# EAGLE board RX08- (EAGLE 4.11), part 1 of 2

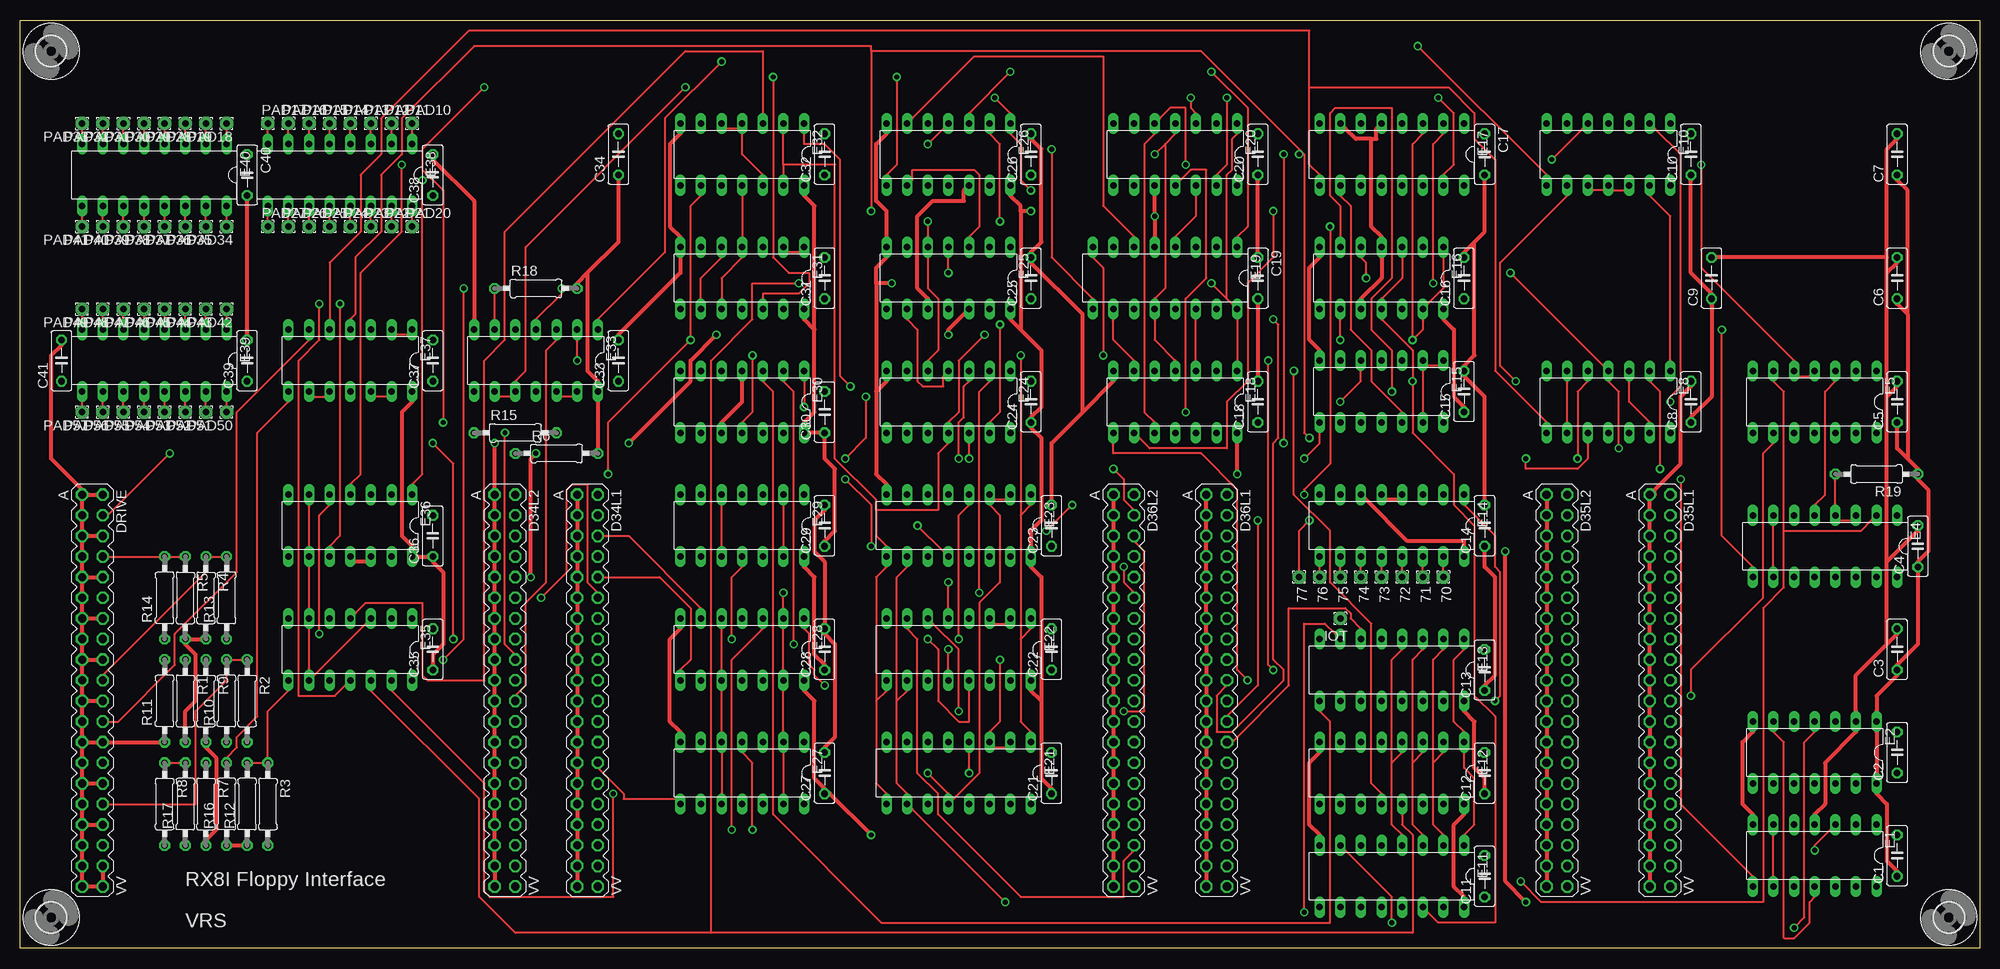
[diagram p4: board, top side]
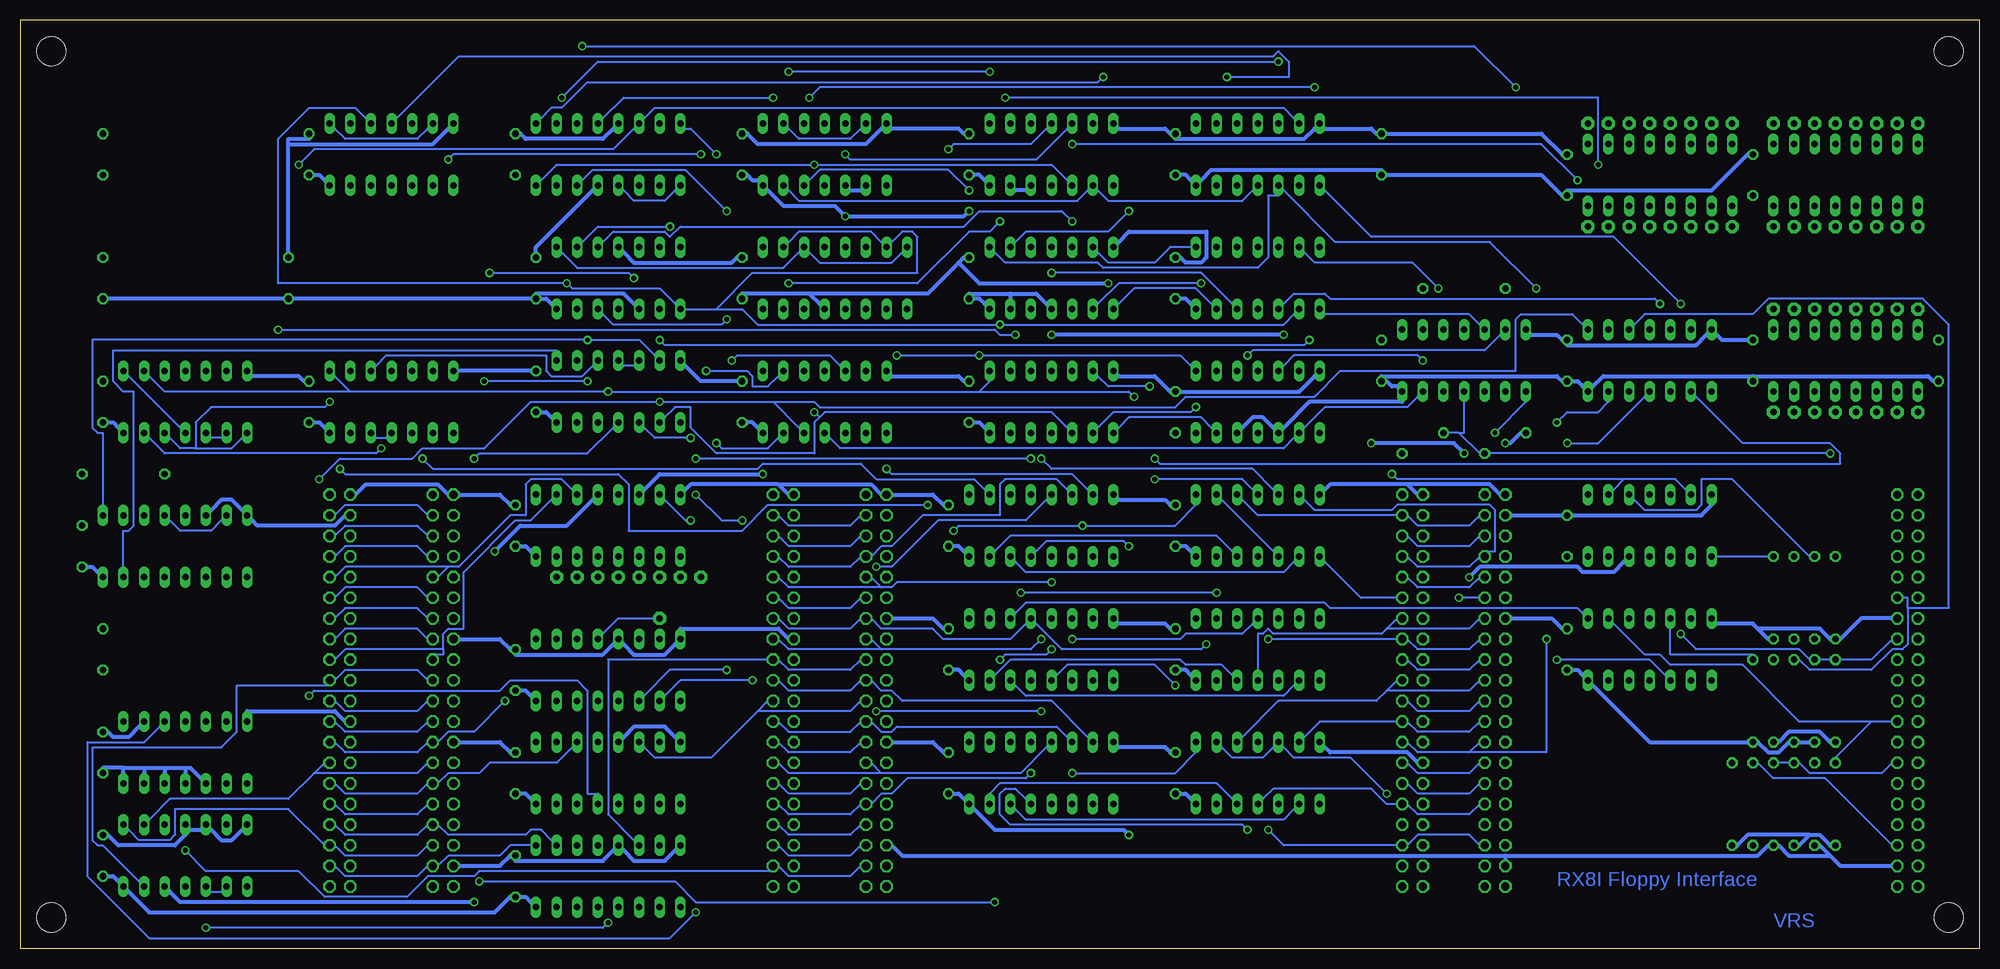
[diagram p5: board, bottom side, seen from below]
Size 241.3 x 114.3 mm. Coordinates in mm from the lower left corner, seen from the top.
Outline: 0,0 0,114.3 241.3,114.3 241.3,0 0,0
Copper layers (1*16): Top 0.035mm / dielectric 1.5mm / Bottom 0.035mm
Design rules "olimex10mil": minimum track width 10mil, minimum drill 24mil, track to track 10mil, track to pad 10mil, pad to pad 10mil, via to via 10mil, smd to smd 10mil, copper to edge 25mil, drill to drill 10mil, minimum pad ring 10mil, minimum via ring 8mil, stop-mask expansion 0mil, vias tented up to drill 0mil, thermal gap 10mil
Net classes: 1 supply: width 0.508 mm

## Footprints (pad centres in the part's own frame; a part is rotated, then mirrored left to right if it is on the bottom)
1,6/0,8 = drill 0.813 pad 1.6 octagon: 1 0,0
C050-025X075 = drill 0.813 octagon: 1 -2.54,0; 2 2.54,0
DEC40PIN = drill 1.016 octagon: A -24.13,-1.27; AA 3.81,-1.27; B -24.13,1.27; BB 3.81,1.27; C -21.59,-1.27; CC 6.35,-1.27; D -21.59,1.27; DD 6.35,1.27; E -19.05,-1.27; EE 8.89,-1.27; F -19.05,1.27; FF 8.89,1.27; H -16.51,-1.27; HH 11.43,-1.27; J -16.51,1.27; JJ 11.43,1.27; K -13.97,-1.27; KK 13.97,-1.27; L -13.97,1.27; LL 13.97,1.27; M -11.43,-1.27; MM 16.51,-1.27; N -11.43,1.27; NN 16.51,1.27; P -8.89,-1.27; PP 19.05,-1.27; R -8.89,1.27; RR 19.05,1.27; S -6.35,-1.27; SS 21.59,-1.27; T -6.35,1.27; TT 21.59,1.27; U -3.81,-1.27; UU 24.13,-1.27; V -3.81,1.27; VV 24.13,1.27; W -1.27,-1.27; X -1.27,1.27; Y 1.27,-1.27; Z 1.27,1.27
DIL14 = drill 0.813 long: 1 -7.62,-3.81; 2 -5.08,-3.81; 3 -2.54,-3.81; 4 0,-3.81; 5 2.54,-3.81; 6 5.08,-3.81; 7 7.62,-3.81; 8 7.62,3.81; 9 5.08,3.81; 10 2.54,3.81; 11 0,3.81; 12 -2.54,3.81; 13 -5.08,3.81; 14 -7.62,3.81
DIL16 = drill 0.813 long: 1 -8.89,-3.81; 2 -6.35,-3.81; 3 -3.81,-3.81; 4 -1.27,-3.81; 5 1.27,-3.81; 6 3.81,-3.81; 7 6.35,-3.81; 8 8.89,-3.81; 9 8.89,3.81; 10 6.35,3.81; 11 3.81,3.81; 12 1.27,3.81; 13 -1.27,3.81; 14 -3.81,3.81; 15 -6.35,3.81; 16 -8.89,3.81
0207/10 = drill 0.813 octagon: 1 -5.08,0; 2 5.08,0
3,6 = hole 3.6: 0,0

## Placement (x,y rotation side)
70  [1,6/0,8]  175.26,45.72 270 top
71  [1,6/0,8]  172.72,45.72 270 top
72  [1,6/0,8]  170.18,45.72 270 top
73  [1,6/0,8]  167.64,45.72 270 top
74  [1,6/0,8]  165.1,45.72 270 top
75  [1,6/0,8]  162.56,45.72 270 top
76  [1,6/0,8]  160.02,45.72 270 top
77  [1,6/0,8]  157.48,45.72 270 top
C1  0.1  [C050-025X075]  231.14,11.43 90 top
C2  0.1  [C050-025X075]  231.14,24.13 90 top
C3  0.1  [C050-025X075]  231.14,36.83 90 top
C4  0.1  [C050-025X075]  233.68,49.53 90 top
C5  0.1  [C050-025X075]  231.14,67.31 90 top
C6  0.1  [C050-025X075]  231.14,82.55 90 top
C7  0.1  [C050-025X075]  231.14,97.79 90 top
C8  0.1  [C050-025X075]  205.74,67.31 90 top
C9  0.1  [C050-025X075]  208.28,82.55 90 top
C10  0.1  [C050-025X075]  205.74,97.79 90 top
C11  0.1  [C050-025X075]  180.34,8.89 90 top
C12  0.1  [C050-025X075]  180.34,21.59 90 top
C13  0.1  [C050-025X075]  180.34,34.29 90 top
C14  0.1  [C050-025X075]  180.34,52.07 90 top
C15  0.1  [C050-025X075]  177.8,68.58 90 top
C16  0.1  [C050-025X075]  177.8,82.55 90 top
C17  0.1  [C050-025X075]  180.34,97.79 270 top
C18  0.1  [C050-025X075]  152.4,67.31 90 top
C19  0.1  [C050-025X075]  152.4,82.55 270 top
C20  0.1  [C050-025X075]  152.4,97.79 90 top
C21  0.1  [C050-025X075]  127,21.59 90 top
C22  0.1  [C050-025X075]  127,36.83 90 top
C23  0.1  [C050-025X075]  127,52.07 90 top
C24  0.1  [C050-025X075]  124.46,67.31 90 top
C25  0.1  [C050-025X075]  124.46,82.55 90 top
C26  0.1  [C050-025X075]  124.46,97.79 90 top
C27  0.1  [C050-025X075]  99.06,21.59 90 top
C28  0.1  [C050-025X075]  99.06,36.83 90 top
C29  0.1  [C050-025X075]  99.06,52.07 90 top
C30  0.1  [C050-025X075]  99.06,66.04 90 top
C31  0.1  [C050-025X075]  99.06,82.55 90 top
C32  0.1  [C050-025X075]  99.06,97.79 90 top
C33  0.1  [C050-025X075]  73.66,72.39 90 top
C34  0.1  [C050-025X075]  73.66,97.79 90 top
C35  0.1  [C050-025X075]  50.8,36.83 90 top
C36  0.1  [C050-025X075]  50.8,50.8 90 top
C37  0.1  [C050-025X075]  50.8,72.39 90 top
C38  0.1  [C050-025X075]  50.8,95.25 90 top
C39  0.1  [C050-025X075]  27.94,72.39 90 top
C40  0.1  [C050-025X075]  27.94,95.25 270 top
C41  0.1  [C050-025X075]  5.08,72.39 90 top
D34L1  [DEC40PIN]  69.85,31.75 270 top
D34L2  [DEC40PIN]  59.69,31.75 270 top
D35L1  [DEC40PIN]  201.93,31.75 270 top
D35L2  [DEC40PIN]  189.23,31.75 270 top
D36L1  [DEC40PIN]  147.32,31.75 270 top
D36L2  [DEC40PIN]  135.89,31.75 270 top
DRIVE  [DEC40PIN]  8.89,31.75 270 top
E1  74LS10N  [DIL14]  220.98,11.43 180 top
E2  74LS74N  [DIL14]  220.98,24.13 180 top
E4  74LS161N  [DIL16]  222.25,49.53 180 top
E5  74LS00N  [DIL14]  220.98,67.31 180 top
E8  74LS10N  [DIL14]  195.58,67.31 180 top
E10  74LS10N  [DIL14]  195.58,97.79 180 top
E11  74LS138N  [DIL16]  168.91,8.89 180 top
E12  74LS138N  [DIL16]  168.91,21.59 180 top
E13  74LS138N  [DIL16]  168.91,34.29 180 top
E14  74LS138N  [DIL16]  168.91,52.07 180 top
E15  74LS00N  [DIL14]  167.64,68.58 180 top
E16  74LS74N  [DIL14]  167.64,82.55 180 top
E17  74LS76N  [DIL16]  168.91,97.79 180 top
E18  74LS02N  [DIL14]  142.24,67.31 180 top
E19  74LS76N  [DIL16]  140.97,82.55 180 top
E20  74HCT32N  [DIL14]  142.24,97.79 180 top
E21  74LS195N  [DIL16]  115.57,21.59 180 top
E22  74LS195N  [DIL16]  115.57,36.83 180 top
E23  74LS195N  [DIL16]  115.57,52.07 180 top
E24  74LS08N  [DIL14]  114.3,67.31 180 top
E25  74LS04N  [DIL14]  114.3,82.55 180 top
E26  74LS32N  [DIL14]  114.3,97.79 180 top
E27  7438N  [DIL14]  88.9,21.59 180 top
E28  7438N  [DIL14]  88.9,36.83 180 top
E29  7438N  [DIL14]  88.9,52.07 180 top
E30  74LS74N  [DIL14]  88.9,67.31 180 top
E31  74LS20N  [DIL14]  88.9,82.55 180 top
E32  74LS27N  [DIL14]  88.9,97.79 180 top
E33  7438N  [DIL14]  63.5,72.39 180 top
E35  74HCT02N  [DIL14]  40.64,36.83 180 top
E36  74HCT02N  [DIL14]  40.64,52.07 180 top
E37  7438N  [DIL14]  40.64,72.39 180 top
E38  SPARE  [DIL16]  39.37,95.25 180 top
E39  SPARE  [DIL16]  16.51,72.39 180 top
E40  SPARE  [DIL16]  16.51,95.25 180 top
IOT  [1,6/0,8]  162.56,40.64 270 top
PAD10  [1,6/0,8]  48.26,101.6 0 top
PAD11  [1,6/0,8]  45.72,101.6 0 top
PAD12  [1,6/0,8]  43.18,101.6 0 top
PAD13  [1,6/0,8]  40.64,101.6 0 top
PAD14  [1,6/0,8]  38.1,101.6 0 top
PAD15  [1,6/0,8]  35.56,101.6 0 top
PAD16  [1,6/0,8]  33.02,101.6 0 top
PAD17  [1,6/0,8]  30.48,101.6 0 top
PAD18  [1,6/0,8]  25.4,101.6 180 top
PAD19  [1,6/0,8]  22.86,101.6 180 top
PAD20  [1,6/0,8]  48.26,88.9 0 top
PAD21  [1,6/0,8]  45.72,88.9 0 top
PAD22  [1,6/0,8]  43.18,88.9 0 top
PAD23  [1,6/0,8]  40.64,88.9 0 top
PAD24  [1,6/0,8]  38.1,88.9 0 top
PAD25  [1,6/0,8]  35.56,88.9 0 top
PAD26  [1,6/0,8]  33.02,88.9 0 top
PAD27  [1,6/0,8]  30.48,88.9 0 top
PAD28  [1,6/0,8]  20.32,101.6 180 top
PAD29  [1,6/0,8]  17.78,101.6 180 top
PAD30  [1,6/0,8]  15.24,101.6 180 top
PAD31  [1,6/0,8]  12.7,101.6 180 top
PAD32  [1,6/0,8]  10.16,101.6 180 top
PAD33  [1,6/0,8]  7.62,101.6 180 top
PAD34  [1,6/0,8]  25.4,88.9 180 top
PAD35  [1,6/0,8]  22.86,88.9 180 top
PAD36  [1,6/0,8]  20.32,88.9 180 top
PAD37  [1,6/0,8]  17.78,88.9 180 top
PAD38  [1,6/0,8]  15.24,88.9 180 top
PAD39  [1,6/0,8]  12.7,88.9 180 top
PAD40  [1,6/0,8]  10.16,88.9 180 top
PAD41  [1,6/0,8]  7.62,88.9 180 top
PAD42  [1,6/0,8]  25.4,78.74 180 top
PAD43  [1,6/0,8]  22.86,78.74 180 top
PAD44  [1,6/0,8]  20.32,78.74 180 top
PAD45  [1,6/0,8]  17.78,78.74 180 top
PAD46  [1,6/0,8]  15.24,78.74 180 top
PAD47  [1,6/0,8]  12.7,78.74 180 top
PAD48  [1,6/0,8]  10.16,78.74 180 top
PAD49  [1,6/0,8]  7.62,78.74 180 top
PAD50  [1,6/0,8]  25.4,66.04 180 top
PAD51  [1,6/0,8]  22.86,66.04 180 top
PAD52  [1,6/0,8]  20.32,66.04 180 top
PAD53  [1,6/0,8]  17.78,66.04 180 top
PAD54  [1,6/0,8]  15.24,66.04 180 top
PAD55  [1,6/0,8]  12.7,66.04 180 top
PAD56  [1,6/0,8]  10.16,66.04 180 top
PAD57  [1,6/0,8]  7.62,66.04 180 top
R1  180  [0207/10]  20.32,30.48 270 top
R2  180  [0207/10]  27.94,30.48 270 top
R3  180  [0207/10]  30.48,17.78 270 top
R4  180  [0207/10]  22.86,43.18 270 top
R5  180  [0207/10]  20.32,43.18 270 top
R6  180  [0207/10]  66.04,60.96 0 top
R7  180  [0207/10]  22.86,17.78 270 top
R8  180  [0207/10]  17.78,17.78 270 top
R9  120  [0207/10]  22.86,30.48 270 top
R10  390  [0207/10]  25.4,30.48 90 top
R11  390  [0207/10]  17.78,30.48 90 top
R12  390  [0207/10]  27.94,17.78 90 top
R13  390  [0207/10]  25.4,43.18 90 top
R14  390  [0207/10]  17.78,43.18 90 top
R15  390  [0207/10]  60.96,63.5 0 top
R16  390  [0207/10]  25.4,17.78 90 top
R17  390  [0207/10]  20.32,17.78 90 top
R18  10K  [0207/10]  63.5,81.28 0 top
R19  10K  [0207/10]  228.6,58.42 180 top
U$1  [3,6]  237.49,3.81 0 top
U$2  [3,6]  237.49,110.49 0 top
U$3  [3,6]  3.81,110.49 0 top
U$4  [3,6]  3.81,3.81 0 top

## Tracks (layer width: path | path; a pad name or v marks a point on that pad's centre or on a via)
8/12  (via drill 0.61)
  Top 0.254: v196.85,61.59 196.85,68.58 195.58,69.85 E8.4 194.94,71.75 v183.51,83.19 | v165.74,82.55 165.74,84.45 165.1,85.09 E16.5
  Bottom 0.254: v196.85,61.59 197.49,60.96 223.52,60.96 225.43,62.87 E5.13 | v165.74,82.55 166.37,83.19 v183.51,83.19
8/12\  (via drill 0.61)
  Top 0.254: E37.9 36.2,67.94 37.47,67.94 E37.10 | v168.91,68.58 168.91,73.66 166.37,76.2 166.37,80.01 168.91,82.55 168.91,103.5 161.93,103.5 161.29,102.87 161.29,92.71 162.56,91.44 162.56,87.63 E16.6 | v101.6,60.33 104.14,62.87 v104.14,67.94 | E10.13 200.66,92.71 203.2,90.17 203.2,72.39 E8.1
  Bottom 0.254: 123.19,68.58 121.92,69.85 E24.1 | 200.66,68.58 v168.91,68.58 123.19,68.58 | 200.66,68.58 202.56,70.48 E8.1 | 200.66,68.58 223.52,68.58 225.43,70.48 E5.2 | v101.6,60.33 100.97,59.69 17.14,59.69 17.14,60.96 18.41,62.23 29.21,62.23 34.92,67.94 E37.9 | v104.14,67.94 104.78,68.58 123.19,68.58
ACB00\
  Bottom 0.254: E29.3 90.81,55.24 88.9,53.34 71.75,53.34 D34L1.D 70.48,53.34 69.22,52.07 62.87,52.07 61.59,53.34 D34L2.D
ACB01\
  Bottom 0.254: E29.6 83.19,55.24 81.92,53.98 72.39,53.98 71.75,54.61 60.33,54.61 59.69,53.98 59.69,48.9 60.96,48.9 D34L2.J 61.59,48.26 62.87,46.99 69.22,46.99 70.48,48.26 D34L1.J
ACB02\  (via drill 0.61)
  Top 0.254: v64.14,43.18 67.31,46.35 67.31,56.52 67.94,57.15 69.85,57.15 69.85,45.09 71.12,43.81 D34L1.N
  Bottom 0.254: E29.8 80.64,47.62 76.2,43.18 71.75,43.18 D34L1.N | v64.14,43.18 61.59,43.18 D34L2.N
ACB03\  (via drill 0.61)
  Top 0.254: v87.63,38.1 87.63,45.72 88.9,46.99 E29.11
  Bottom 0.254: v87.63,38.1 71.75,38.1 D34L1.T 70.48,38.1 69.22,36.83 62.87,36.83 61.59,38.1 D34L2.T
ACB04\
  Bottom 0.254: 73.03,31.75 71.75,33.02 D34L1.X | 73.03,31.75 74.3,30.48 86.36,30.48 90.81,26.04 E27.3 | 73.03,31.75 62.87,31.75 61.59,33.02 D34L2.X
ACB05\
  Bottom 0.254: E27.6 83.19,26.04 81.28,27.94 71.75,27.94 D34L1.BB 70.48,27.94 69.22,26.67 62.87,26.67 61.59,27.94 D34L2.BB
ACB06\
  Top 0.254: E27.8 80.64,18.41 74.3,18.41 74.3,19.05 71.12,22.23 D34L1.FF
  Bottom 0.254: D34L2.FF 61.59,22.86 62.87,21.59 69.22,21.59 70.48,22.86 D34L1.FF
ACB07\
  Bottom 0.254: E27.11 88.27,18.41 87,19.68 74.93,19.68 73.03,17.78 71.75,17.78 D34L1.LL 70.48,17.78 69.22,16.51 62.87,16.51 61.59,17.78 D34L2.LL
ACB08\  (via drill 0.61)
  Top 0.254: v87.63,14.61 87.63,35.56 91.44,39.37 E28.3
  Bottom 0.254: v87.63,14.61 85.72,12.7 71.75,12.7 D34L1.RR 70.48,12.7 69.22,13.97 62.87,13.97 61.59,12.7 D34L2.RR
ACB09\
  Top 0.254: E28.6 83.82,41.91 74.93,50.8 71.75,50.8 D34L1.F
  Bottom 0.254: D34L2.F 61.59,50.8 62.87,49.53 69.22,49.53 70.48,50.8 D34L1.F
ACB10\
  Top 0.254: E28.8 81.28,34.29 82.55,35.56 82.55,41.91 78.74,45.72 71.75,45.72 D34L1.L
  Bottom 0.254: D34L2.L 61.59,45.72 62.87,44.45 69.22,44.45 70.48,45.72 D34L1.L
ACB11\
  Bottom 0.254: 73.03,39.37 71.75,40.64 D34L1.R | 73.03,39.37 73.66,38.73 87,38.73 87.63,39.37 88.27,38.73 88.9,38.73 88.9,34.29 E28.11 | 73.03,39.37 62.87,39.37 61.59,40.64 D34L2.R
ACCLEAR\  (via drill 0.61)
  Top 0.254: v50.8,62.23 53.34,59.69 v53.34,38.1
  Bottom 0.254: 62.87,24.13 61.59,25.4 D34L2.DD | 62.87,24.13 69.22,24.13 70.48,25.4 D34L1.DD | v50.8,62.23 46.99,62.23 41.27,67.94 E37.11 | v53.34,38.1 53.34,24.13 62.87,24.13
BAC00  (via drill 0.61)
  Top 0.254: v134.62,59.05 135.89,57.78 135.89,55.24 137.16,53.98 D36L2.D
  Bottom 0.254: v134.62,59.05 133.99,58.42 111.76,58.42 109.86,56.52 E23.7 | D36L1.D 147.96,53.34 146.69,52.07 139.06,52.07 137.79,53.34 D36L2.D
BAC01
  Bottom 0.254: E23.6 112.39,56.52 113.67,57.78 120.02,57.78 120.65,57.15 120.65,53.34 130.18,53.34 133.99,49.53 135.25,49.53 136.53,48.26 D36L2.J 137.79,48.26 139.06,46.99 146.69,46.99 147.96,48.26 D36L1.J
BAC02  (via drill 0.61)
  Top 0.254: v135.89,46.99 135.89,45.09 137.16,43.81 D36L2.N
  Bottom 0.254: v135.89,46.99 133.99,46.99 128.27,52.7 117.47,52.7 114.94,55.24 E23.5 | D36L1.N 147.96,43.18 146.69,41.91 139.06,41.91 137.79,43.18 D36L2.N
BAC03  (via drill 0.61)
  Top 0.254: v115.57,38.1 115.57,53.34 116.84,54.61 E23.4
  Bottom 0.254: v115.57,38.1 116.84,36.83 135.25,36.83 | 135.25,36.83 136.53,38.1 D36L2.T | 135.25,36.83 146.69,36.83 147.96,38.1 D36L1.T
BAC04  (via drill 0.61)
  Top 0.254: v154.31,77.47 154.94,76.83 154.94,62.87 154.31,62.23 154.31,35.56 155.57,34.29 155.57,33.02 149.22,26.67 147.32,26.67 147.32,31.11 148.59,32.38 D36L1.X
  Bottom 0.254: E21.7 109.86,26.04 114.3,30.48 132.72,30.48 133.99,31.75 135.25,31.75 136.53,33.02 D36L2.X 137.79,33.02 139.06,31.75 146.69,31.75 147.96,33.02 D36L1.X | v154.31,77.47 154.94,76.83 168.28,76.83 169.54,78.11 E16.12
BAC05  (via drill 0.61)
  Top 0.254: v161.29,88.9 161.29,59.69 158.12,56.52 v158.12,55.88 | v152.4,52.7 152.4,32.38 148.59,28.57 D36L1.BB
  Bottom 0.254: E21.6 112.39,26.04 113.67,27.3 133.35,27.3 133.99,26.67 135.25,26.67 136.53,27.94 D36L2.BB 137.79,27.94 139.06,26.67 146.69,26.67 147.96,27.94 D36L1.BB | v161.29,88.9 170.18,88.9 172.09,87 E16.2 | v158.12,55.88 154.94,52.7 v152.4,52.7
BAC06
  Bottom 0.254: 135.25,21.59 118.11,21.59 114.94,24.77 E21.5 | 135.25,21.59 136.53,22.86 D36L2.FF | 135.25,21.59 146.69,21.59 147.96,22.86 D36L1.FF
BAC07  (via drill 0.61)
  Top 0.254: v116.84,21.59 116.84,24.13 E21.4
  Bottom 0.254: v116.84,21.59 117.47,20.95 132.08,20.95 133.99,19.05 135.25,19.05 136.53,17.78 D36L2.LL 137.79,17.78 139.06,16.51 146.69,16.51 147.96,17.78 D36L1.LL
BAC08
  Top 0.254: E22.7 109.22,39.37 110.49,38.1 110.49,21.59 113.03,19.05 113.03,16.51 123.19,6.35 135.89,6.35 135.89,10.79 137.16,12.06 D36L2.RR
  Bottom 0.254: D36L1.RR 147.96,12.7 146.69,11.43 139.06,11.43 137.79,12.7 D36L2.RR
BAC09  (via drill 0.61)
  Top 0.254: v115.57,29.21 115.57,36.83 112.39,40.01 E22.6 | v135.89,29.21 138.43,29.21 138.43,48.9 137.16,50.16 D36L2.F
  Bottom 0.254: v115.57,29.21 v135.89,29.21 | D36L1.F 147.96,50.8 146.69,49.53 139.06,49.53 137.79,50.8 D36L2.F
BAC10  (via drill 0.61)
  Top 0.254: v114.3,45.09 114.3,41.91 E22.5
  Bottom 0.254: v114.3,45.09 133.35,45.09 133.99,44.45 135.25,44.45 | 135.25,44.45 136.53,45.72 D36L2.L | 135.25,44.45 146.69,44.45 147.96,45.72 D36L1.L
BAC11  (via drill 0.61)
  Top 0.254: v95.25,37.47 95.25,68.58 93.98,69.85 E30.2
  Bottom 0.254: D36L1.R 147.96,40.64 146.69,39.37 139.06,39.37 137.79,40.64 D36L2.R 136.53,40.64 135.25,39.37 128.91,39.37 127.64,38.1 119.38,38.1 117.47,40.01 E22.4 116.2,40.01 113.03,36.83 95.89,36.83 v95.25,37.47
BINIT  (via drill 0.61)
  Top 0.254: v220.98,12.06 220.98,12.7 222.88,14.61 E1.3
  Bottom 0.254: v220.98,12.06 218.44,9.53 207.01,9.53 203.84,6.35 193.68,6.35 191.13,8.89 185.42,8.89 184.78,9.53 148.59,9.53 D36L1.TT 147.96,10.16 146.69,8.89 139.06,8.89 137.79,10.16 D36L2.TT
BIOP1
  Bottom 0.254: E11.6 165.74,13.34 168.91,16.51 168.91,35.56 149.22,35.56 D36L1.V 147.96,35.56 146.69,34.29 139.06,34.29 137.79,35.56 D36L2.V
BIOP2
  Bottom 0.254: 150.5,29.21 149.22,30.48 D36L1.Z | 150.5,29.21 156.21,23.5 163.19,23.5 164.47,24.77 E12.6 | 150.5,29.21 139.06,29.21 137.79,30.48 D36L2.Z
BIOP4
  Top 0.254: E13.6 165.1,39.37 163.83,40.64 163.83,41.27 163.19,41.91 156.21,41.91 156.21,32.38 149.22,25.4 D36L1.DD
  Bottom 0.254: D36L2.DD 137.79,25.4 139.06,24.13 146.69,24.13 147.96,25.4 D36L1.DD
BMB00
  Bottom 0.254: D35L2.D 191.13,53.34 192.41,54.61 201.29,54.61 202.56,53.34 D35L1.D
BMB01
  Bottom 0.254: D35L2.J 191.13,48.26 192.41,49.53 201.29,49.53 202.56,48.26 D35L1.J
BMB02
  Bottom 0.254: D35L2.N 191.13,43.18 192.41,44.45 201.29,44.45 202.56,43.18 D35L1.N
BMB03
  Bottom 0.254: E1.13 226.69,8.26 231.14,12.7 231.78,12.7 232.41,13.34 232.41,24.77 216.53,24.77 214.63,26.67 214.63,32.38 203.2,32.38 D35L1.X 202.56,33.02 201.29,34.29 192.41,34.29 191.13,33.02 D35L2.X
BMB03\
  Bottom 0.254: D35L2.T 191.13,38.1 192.41,39.37 201.29,39.37 202.56,38.1 D35L1.T
BMB04
  Bottom 0.254: 205.1,21.59 203.84,22.86 D35L1.FF | 205.1,21.59 208.28,18.41 222.88,18.41 225.43,15.88 E1.2 | 205.1,21.59 192.41,21.59 191.13,22.86 D35L2.FF
BMB04\
  Bottom 0.254: D35L2.BB 191.13,27.94 192.41,26.67 201.29,26.67 202.56,27.94 D35L1.BB
BMB05
  Bottom 0.254: E1.1 227.97,14.61 226.69,13.34 222.88,13.34 222.25,13.97 222.25,17.14 208.28,17.14 203.84,12.7 D35L1.RR 202.56,12.7 201.29,11.43 192.41,11.43 191.13,12.7 D35L2.RR
BMB05\
  Bottom 0.254: D35L2.LL 191.13,17.78 192.41,16.51 201.29,16.51 202.56,17.78 D35L1.LL
BMB06
  Bottom 0.254: 188.59,46.99 187.32,46.99 180.97,53.34 179.07,53.34 179.07,57.15 178.44,57.78 174.62,57.78 173.35,56.52 E14.3 | 188.59,46.99 189.87,45.72 D35L2.L | 188.59,46.99 201.29,46.99 202.56,45.72 D35L1.L
BMB06\
  Bottom 0.254: D35L2.F 191.13,50.8 192.41,52.07 201.29,52.07 202.56,50.8 D35L1.F
BMB07
  Bottom 0.254: 189.23,36.83 189.23,36.2 190.5,36.2 D35L2.V | 189.23,36.83 189.23,38.73 188.59,39.37 186.69,39.37 186.69,46.35 180.34,52.7 178.44,52.7 175.9,55.24 E14.2 | 189.23,36.83 201.29,36.83 202.56,35.56 D35L1.V
BMB07\
  Bottom 0.254: D35L2.R 191.13,40.64 192.41,41.91 201.29,41.91 202.56,40.64 D35L1.R
BMB08  (via drill 0.61)
  Top 0.254: v181.61,30.48 182.25,31.11 182.25,46.35 181.61,46.99 181.61,50.8 177.8,54.61 E14.1
  Bottom 0.254: v181.61,30.48 185.42,26.67 188.59,26.67 189.87,25.4 D35L2.DD 191.13,25.4 192.41,24.13 201.29,24.13 202.56,25.4 D35L1.DD
BMB08\
  Bottom 0.254: D35L2.Z 191.13,30.48 192.41,29.21 201.29,29.21 202.56,30.48 D35L1.Z
BMB09
  Top 0.254: 171.45,22.86 171.45,15.24 172.72,13.97 E11.3 | 171.45,22.86 172.72,24.13 E12.3 | 171.45,22.86 171.45,35.56 172.72,36.83 E13.3
  Bottom 0.254: D35L1.JJ 202.56,20.32 201.29,19.05 192.41,19.05 191.13,20.32 D35L2.JJ 189.87,20.32 188.59,21.59 184.78,21.59 183.51,22.86 175.26,22.86 173.35,24.77 E12.3
BMB10
  Top 0.254: 173.99,22.86 173.99,15.24 175.26,13.97 E11.2 | 173.99,22.86 175.26,24.13 E12.2 | 173.99,22.86 173.99,35.56 175.26,36.83 E13.2
  Bottom 0.254: D35L1.NN 202.56,15.24 201.29,13.97 192.41,13.97 191.13,15.24 D35L2.NN 189.87,15.24 188.59,13.97 179.07,13.97 178.44,14.61 177.16,14.61 175.9,13.34 E11.2
BMB11
  Top 0.254: E11.1 177.8,13.97 179.07,15.24 179.07,20.95 177.8,22.23 177.8,24.13 E12.1 177.8,26.67 176.53,27.94 176.53,35.56 177.8,36.83 E13.1
  Bottom 0.254: D35L1.TT 202.56,10.16 201.29,8.89 192.41,8.89 191.13,10.16 D35L2.TT 189.87,10.16 188.59,11.43 182.25,11.43 180.97,12.7 178.44,12.7 E11.1
BRUN\
  Bottom 0.254: D34L2.JJ 61.59,20.32 62.87,19.05 69.22,19.05 70.48,20.32 D34L1.JJ
BTS1
  Bottom 0.254: D36L2.NN 137.79,15.24 139.06,13.97 146.69,13.97 147.96,15.24 D36L1.NN
BTS3
  Bottom 0.254: D36L2.JJ 137.79,20.32 139.06,19.05 146.69,19.05 147.96,20.32 D36L1.JJ
CLK_BUF  (via drill 0.61)
  Top 0.254: 107.95,30.48 107.95,20.32 109.22,19.05 E21.10 109.86,17.14 v121.28,5.71 | 107.95,30.48 109.22,31.75 E22.10 | 107.95,30.48 107.95,45.72 109.22,46.99 E23.10 | 217.17,51.44 226.69,51.44 227.97,52.7 E4.2 | 217.17,51.44 217.17,68.58 215.9,69.85 E5.6 | v184.78,8.26 187.32,5.71 214.63,5.71 214.63,41.91 217.17,44.45 217.17,51.44
  Bottom 0.254: v121.28,5.71 158.12,5.71 160.66,8.26 v184.78,8.26
CLK_PARITY\  (via drill 0.61)
  Top 0.254: E5.4 220.34,70.48 219.07,70.48 E5.5 218.44,72.39 207.01,83.82 v207.01,96.52
  Bottom 0.254: E32.6 84.45,102.23 85.72,103.5 163.19,103.5 164.47,102.23 E17.6 165.74,100.97 168.28,98.42 205.1,98.42 v207.01,96.52
DONE  (via drill 0.61)
  Top 0.254: E25.3 116.84,87.63 118.11,88.9 118.11,95.25 117.47,95.89 109.86,95.89 109.86,94.61 E26.9 | v148.59,104.78 148.59,96.52 147.32,95.25 E20.13 | E32.11 88.9,92.71 88.9,87.63 E31.4 88.9,85.09 86.36,82.55 86.36,80.01 E31.10 | v39.37,79.38 39.37,50.8 38.1,49.53 E36.10
  Bottom 0.254: E20.13 146.69,93.34 145.41,92.08 111.12,92.08 109.86,93.34 E26.9 108.58,93.34 107.31,92.08 90.81,92.08 89.53,93.34 E32.11 | v148.59,104.78 167,104.78 169.54,102.23 E17.4 | v39.37,79.38 40.01,80.01 80.01,80.01 80.64,80.64 84.45,80.64 85.72,79.38 E31.10
DONE\  (via drill 0.61)
  Top 0.254: v114.3,83.19 114.3,85.09 E25.4 | v92.71,107.31 92.71,85.09 94.61,83.19 97.16,83.19 97.16,81.92 95.89,80.64 91.44,80.64 91.44,80.01 E31.12
  Bottom 0.254: v114.3,83.19 95.89,83.19 92.08,79.38 E31.12 | v92.71,107.31 85.09,107.31 85.09,109.22 86.36,110.49 87,109.86 187.32,109.86 194.94,102.23 E10.4
DONE_FF  (via drill 0.61)
  Top 0.254: v86.36,109.22 79.38,102.23 79.38,85.72 71.12,77.47 E33.1 | v174.62,104.78 176.53,102.87 176.53,96.52 175.26,95.25 E17.15
  Bottom 0.254: v86.36,109.22 170.18,109.22 v174.62,104.78
DONE_SKIP  (via drill 0.61)
  Top 0.254: E18.10 139.7,64.77 138.43,66.04 138.43,99.06 139.7,100.33 E20.5 140.34,102.23 141.6,103.5 143.51,103.5 v143.51,96.52
  Bottom 0.254: E26.10 112.39,94.61 114.3,96.52 v143.51,96.52 175.26,96.52 177.16,94.61 E17.16
ENB_BUF_LD\  (via drill 0.61)
  Top 0.254: 93.98,96.52 93.98,100.33 E32.2 | 93.98,96.52 93.98,95.25 E32.13 | 105.41,30.48 105.41,20.32 106.68,19.05 E21.9 | 105.41,30.48 106.68,31.75 E22.9 | 105.41,30.48 105.41,45.72 106.68,46.99 E23.9 106.68,49.53 105.41,50.8 105.41,53.98 | 93.98,96.52 100.33,96.52 100.33,60.33 105.41,55.24 105.41,53.98 | v209.55,76.2 209.55,50.8 213.36,46.99 E4.9 | v118.75,75.56 115.57,72.39 115.57,66.04 114.3,64.77 E24.11 114.3,62.23 113.03,60.96 113.03,53.98 105.41,53.98
  Bottom 0.254: v209.55,76.2 121.28,76.2 120.65,75.56 v118.75,75.56
ERR_SKIP  (via drill 0.61)
  Top 0.254: E18.4 142.24,72.39 139.7,74.93 139.7,77.47 E19.12 139.7,80.01 140.97,81.28 140.97,99.06 | 140.97,99.06 142.24,100.33 E20.4 | v139.7,97.79 140.97,99.06
  Bottom 0.254: v139.7,97.79 139.06,97.16 116.2,97.16 112.39,100.97 E26.5
ERROR  (via drill 0.61)
  Top 0.254: v49.53,94.61 49.53,58.42 48.26,57.15 E36.1 | v111.76,99.06 113.67,100.97 E26.4 | v127,98.42 127,85.09 132.08,80.01 E19.9
  Bottom 0.254: v49.53,94.61 53.98,99.06 v111.76,99.06 | v127,98.42 126.36,99.06 116.84,99.06 114.94,100.97 E26.4
GND  (via drill 0.61)
  Top 0.508: R16.1 26.04,12.7 27.3,12.7 R12.1 | R11.1 17.14,25.4 10.79,25.4 DRIVE.DD 9.53,25.4 8.26,25.4 DRIVE.CC | DRIVE.MM 7.62,14.61 7.62,13.34 DRIVE.PP 7.62,12.06 7.62,10.79 DRIVE.SS 7.62,9.53 7.62,8.26 DRIVE.UU 8.26,7.62 9.53,7.62 DRIVE.VV 10.16,8.26 10.16,9.53 DRIVE.TT | DRIVE.NN 9.53,15.24 8.26,15.24 DRIVE.MM | DRIVE.MM 7.62,15.88 7.62,17.14 DRIVE.KK 7.62,18.41 7.62,19.68 DRIVE.HH | DRIVE.JJ 9.53,20.32 8.26,20.32 DRIVE.HH | DRIVE.HH 7.62,20.95 7.62,22.23 DRIVE.EE 7.62,23.5 7.62,24.77 DRIVE.CC | DRIVE.CC 7.62,26.04 7.62,27.3 DRIVE.AA 7.62,28.57 7.62,29.84 DRIVE.Y | DRIVE.Z 9.53,30.48 8.26,30.48 DRIVE.Y | DRIVE.Y 7.62,31.11 7.62,32.38 DRIVE.W 7.62,33.66 7.62,34.92 DRIVE.U | DRIVE.V 9.53,35.56 8.26,35.56 DRIVE.U | DRIVE.U 7.62,36.2 7.62,37.47 DRIVE.S 7.62,38.73 7.62,40.01 DRIVE.P | DRIVE.P 7.62,41.27 7.62,42.55 DRIVE.M 7.62,43.81 7.62,45.09 DRIVE.K | DRIVE.L 9.53,45.72 8.26,45.72 DRIVE.K | DRIVE.K 7.62,46.35 7.62,47.62 DRIVE.H 7.62,48.9 7.62,50.16 DRIVE.E | DRIVE.F 9.53,50.8 8.26,50.8 DRIVE.E | DRIVE.E 7.62,51.44 7.62,52.7 DRIVE.C 7.62,53.98 7.62,55.24 DRIVE.A | DRIVE.B 9.53,55.88 8.26,55.88 DRIVE.A | DRIVE.R 9.53,40.64 8.26,40.64 DRIVE.P | D34L2.UU 58.42,8.26 58.42,9.53 D34L2.SS 58.42,10.79 58.42,12.06 D34L2.PP 58.42,13.34 58.42,14.61 D34L2.MM 58.42,15.88 58.42,17.14 D34L2.KK 58.42,18.41 58.42,19.68 D34L2.HH 58.42,20.95 58.42,22.23 D34L2.EE 58.42,23.5 58.42,24.77 D34L2.CC 58.42,26.04 58.42,27.3 D34L2.AA 58.42,28.57 58.42,29.84 D34L2.Y 58.42,31.11 58.42,32.38 D34L2.W 58.42,33.66 58.42,34.92 D34L2.U 58.42,36.2 58.42,37.47 D34L2.S 58.42,38.73 58.42,40.01 D34L2.P 58.42,41.27 58.42,42.55 D34L2.M 58.42,43.81 58.42,45.09 D34L2.K 58.42,46.35 58.42,47.62 D34L2.H 58.42,48.9 58.42,50.16 D34L2.E 58.42,51.44 58.42,52.7 D34L2.C 58.42,53.98 58.42,55.24 D34L2.A 58.42,56.52 v58.42,62.23
  Top 0.508: D34L1.UU 68.58,8.26 68.58,9.53 D34L1.SS 68.58,10.79 68.58,12.06 D34L1.PP 68.58,13.34 68.58,14.61 D34L1.MM 68.58,15.88 68.58,17.14 D34L1.KK 68.58,18.41 68.58,19.68 D34L1.HH 68.58,20.95 68.58,22.23 D34L1.EE 68.58,23.5 68.58,24.77 D34L1.CC 68.58,26.04 68.58,27.3 D34L1.AA 68.58,28.57 68.58,29.84 D34L1.Y 68.58,31.11 68.58,32.38 D34L1.W 68.58,33.66 68.58,34.92 D34L1.U 68.58,36.2 68.58,37.47 D34L1.S 68.58,38.73 68.58,40.01 D34L1.P 68.58,41.27 68.58,42.55 D34L1.M 68.58,43.81 68.58,45.09 D34L1.K 68.58,46.35 68.58,47.62 D34L1.H 68.58,48.9 68.58,50.16 D34L1.E 68.58,51.44 68.58,52.7 D34L1.C 68.58,53.98 68.58,55.24 D34L1.A | E28.7 81.28,39.37 80.01,38.1 80.01,27.94 81.28,26.67 E27.7 | C38.2 50.8,97.16 55.88,92.08 55.88,77.47 E33.7 | C40.2 27.94,92.08 27.94,75.56 C39.2 | C33.2 73.66,75.56 81.28,83.19 81.28,85.09 E31.7 81.28,87.63 80.01,88.9 80.01,99.06 81.28,100.33 E32.7 | C27.2 99.06,24.77 100.33,26.04 100.33,37.47 99.06,38.73 C28.2 99.06,40.01 99.06,47.62 97.79,48.9 97.79,52.7 99.06,53.98 C29.2 | 105.41,68.58 105.41,58.42 106.68,57.15 E23.8 | 105.41,68.58 106.68,69.85 E24.7 | 105.41,81.92 105.41,68.58 | 105.41,81.92 105.41,83.82 106.68,85.09 E25.7 106.68,87.63 106.68,90.81 105.41,92.08 105.41,99.06 106.68,100.33 E26.7 | DRIVE.A 7.62,56.52 3.81,60.33 3.81,73.03 5.08,74.3 C41.2 | C18.2 152.4,70.48 152.4,79.38 C19.2 | E16.7 160.02,85.09 158.75,83.82 158.75,74.93 160.02,73.66 E15.7 | C26.2 124.46,99.69 125.73,98.42 125.73,87 124.46,85.72 C25.2 124.46,84.45 130.81,78.11 130.81,66.04 | D36L2.UU 134.62,8.26 134.62,9.53 D36L2.SS 134.62,10.79 134.62,12.06 D36L2.PP 134.62,13.34 134.62,14.61 D36L2.MM 134.62,15.88 134.62,17.14 D36L2.KK 134.62,18.41 134.62,19.68 D36L2.HH 134.62,20.95 134.62,22.23 D36L2.EE 134.62,23.5 134.62,24.77 D36L2.CC 134.62,26.04 134.62,27.3 D36L2.AA 134.62,28.57 134.62,29.84 D36L2.Y 134.62,31.11 134.62,32.38 D36L2.W 134.62,33.66 134.62,34.92 D36L2.U 134.62,36.2 134.62,37.47 D36L2.S 134.62,38.73 134.62,40.01 D36L2.P 134.62,41.27 134.62,42.55 D36L2.M 134.62,43.81 134.62,45.09 D36L2.K 134.62,46.35 134.62,47.62 D36L2.H 134.62,48.9 134.62,50.16 D36L2.E 134.62,51.44 134.62,52.7 D36L2.C 134.62,53.98 134.62,55.24 D36L2.A
  Top 0.508: 130.81,66.04 127,62.23 127,55.24 C23.2 | 130.81,66.04 134.62,69.85 E18.7 | D35L1.UU 200.66,8.26 200.66,9.53 D35L1.SS 200.66,10.79 200.66,12.06 D35L1.PP 200.66,13.34 200.66,14.61 D35L1.MM 200.66,15.88 200.66,17.14 D35L1.KK 200.66,18.41 200.66,19.68 D35L1.HH 200.66,20.95 200.66,22.23 D35L1.EE 200.66,23.5 200.66,24.77 D35L1.CC 200.66,26.04 200.66,27.3 D35L1.AA 200.66,28.57 200.66,29.84 D35L1.Y 200.66,31.11 200.66,32.38 D35L1.W 200.66,33.66 200.66,34.92 D35L1.U 200.66,36.2 200.66,37.47 D35L1.S 200.66,38.73 200.66,40.01 D35L1.P 200.66,41.27 200.66,42.55 D35L1.M 200.66,43.81 200.66,45.09 D35L1.K 200.66,46.35 200.66,47.62 D35L1.H 200.66,48.9 200.66,50.16 D35L1.E 200.66,51.44 200.66,52.7 D35L1.C 200.66,53.98 200.66,55.24 D35L1.A 201.29,55.88 201.29,56.52 204.47,59.69 204.47,67.94 205.74,69.22 C8.2 | E2.7 213.36,26.67 212.09,25.4 212.09,17.78 213.36,16.51 E1.7 | 229.87,37.47 226.06,33.66 226.06,29.21 E2.2 226.06,26.67 222.25,22.86 222.25,17.78 220.98,16.51 E1.4 | 229.87,37.47 231.14,38.73 C3.2 | 229.87,47.62 233.68,51.44 C4.2 | 229.87,37.47 229.87,47.62 | 229.87,67.94 231.14,69.22 C5.2 | 229.87,47.62 229.87,67.94 | 229.87,83.19 231.14,84.45 C6.2 | 229.87,67.94 229.87,83.19 | 229.87,83.19 229.87,85.09 | 229.87,85.09 229.87,98.42 231.14,99.69 C7.2 | 229.87,85.09 208.91,85.09 C9.2 | D36L1.UU 146.05,8.26 146.05,9.53 D36L1.SS 146.05,10.79 146.05,12.06 D36L1.PP 146.05,13.34 146.05,14.61 D36L1.MM 146.05,15.88 146.05,17.14 D36L1.KK 146.05,18.41 146.05,19.68 D36L1.HH 146.05,20.95 146.05,22.23 D36L1.EE 146.05,23.5 146.05,24.77 D36L1.CC 146.05,26.04 146.05,27.3 D36L1.AA 146.05,28.57 146.05,29.84 D36L1.Y 146.05,31.11 146.05,32.38 D36L1.W 146.05,33.66 146.05,34.92 D36L1.U 146.05,36.2 146.05,37.47 D36L1.S 146.05,38.73 146.05,40.01 D36L1.P 146.05,41.27 146.05,42.55 D36L1.M 146.05,43.81 146.05,45.09 D36L1.K 146.05,46.35 146.05,47.62 D36L1.H 146.05,48.9 146.05,50.16 D36L1.E 146.05,51.44 146.05,52.7 D36L1.C 146.05,53.98 146.05,55.24 D36L1.A
  Top 0.508: D35L2.UU 187.96,8.26 187.96,9.53 D35L2.SS 187.96,10.79 187.96,12.06 D35L2.PP 187.96,13.34 187.96,14.61 D35L2.MM 187.96,15.88 187.96,17.14 D35L2.KK 187.96,18.41 187.96,19.68 D35L2.HH 187.96,20.95 187.96,22.23 D35L2.EE 187.96,23.5 187.96,24.77 D35L2.CC 187.96,26.04 187.96,27.3 D35L2.AA 187.96,28.57 187.96,29.84 D35L2.Y 187.96,31.11 187.96,32.38 D35L2.W 187.96,33.66 187.96,34.92 D35L2.U 187.96,36.2 187.96,37.47 D35L2.S 187.96,38.73 187.96,40.01 D35L2.P 187.96,41.27 187.96,42.55 D35L2.M 187.96,43.81 187.96,45.09 D35L2.K 187.96,46.35 187.96,47.62 D35L2.H 187.96,48.9 187.96,50.16 D35L2.E 187.96,51.44 187.96,52.7 D35L2.C 187.96,53.98 187.96,55.24 D35L2.A | E12.8 160.02,24.13 158.75,22.86 158.75,15.24 160.02,13.97 E11.8 | 179.07,87 180.34,88.27 180.34,94.61 C17.2 | 179.07,87 177.8,85.72 C16.2 | 179.07,87 179.07,73.03 177.8,71.75 C15.2 177.8,70.48 180.34,67.94 180.34,55.24 C14.2 | v107.31,81.92 105.41,81.92
  Bottom 0.508: 18.41,11.43 17.14,10.16 10.79,10.16 DRIVE.TT | 18.41,11.43 19.68,12.7 R17.1 | 18.41,11.43 23.5,11.43 24.77,12.7 R16.1 26.04,12.7 27.3,11.43 58.42,11.43 | R10.1 24.77,25.4 23.5,26.67 19.68,26.67 18.41,25.4 R11.1 | DRIVE.R 10.79,40.64 14.61,40.64 17.14,38.1 R14.1 18.41,38.1 19.68,39.37 27.3,39.37 | 27.3,39.37 27.94,40.01 32.38,40.01 E35.7 | 27.3,39.37 26.04,38.1 R13.1 | D34L2.C 57.78,53.34 51.44,53.34 C36.2 50.16,53.34 34.29,53.34 33.02,54.61 E36.7 | C35.2 51.44,39.37 52.7,40.64 57.78,40.64 D34L2.P | 70.48,57.15 80.01,57.15 80.64,56.52 E29.7 | 70.48,57.15 69.22,55.88 D34L1.A | E27.7 80.64,24.77 80.01,24.13 70.48,24.13 69.22,22.86 D34L1.EE | 70.48,57.15 60.33,57.15 59.05,55.88 D34L2.A | E33.7 55.24,75.56 52.07,75.56 51.44,74.93 C37.2 50.8,74.3 34.92,74.3 33.66,75.56 E37.7 32.38,75.56 31.75,74.93 28.57,74.93 C39.2 | E26.7 106.05,100.97 100.33,100.97 99.69,100.33 C32.2 99.06,99.69 83.19,99.69 81.92,100.97 E32.7 80.64,100.97 74.93,100.97 74.3,100.33 C34.2 73.03,100.33 53.98,100.33 51.44,97.79 C38.2 | C31.2 98.42,85.09 97.79,84.45 95.89,84.45 95.25,85.09 95.25,88.27 104.78,88.27 106.05,87 E25.7 | C27.2 99.69,24.13 100.33,24.77 106.05,24.77 E21.8 | C28.2 99.69,39.37 100.33,40.01 106.05,40.01 E22.8 | C29.2 99.69,54.61 100.33,55.24 106.05,55.24 E23.8 | E24.7 106.05,70.48 101.6,70.48 99.69,68.58 C30.2 98.42,68.58 83.82,68.58 81.92,70.48 E30.7 | C26.2 125.09,100.33 125.73,100.97 133.99,100.97 E20.7 135.25,100.97 137.16,99.06 150.5,99.06 151.76,100.33 C20.2 | 144.15,80.64 142.88,79.38 E19.13 | 144.15,80.64 152.4,80.64 C19.2 | E15.7 159.38,71.75 157.48,69.85 153.03,69.85 C18.2
  Bottom 0.508: 125.73,84.45 125.09,85.09 C25.2 | 125.73,84.45 129.54,80.64 144.15,80.64 | C21.2 127.64,24.13 128.91,25.4 133.99,25.4 D36L2.CC | C24.2 125.09,69.85 125.73,70.48 133.99,70.48 E18.7 | C23.2 127.64,54.61 128.91,55.88 133.99,55.88 D36L2.A 135.25,55.88 136.53,57.15 147.96,57.15 | C22.2 127.64,39.37 128.91,40.64 133.99,40.64 D36L2.P | C8.2 206.38,69.85 207.01,70.48 212.72,70.48 E5.7 | E4.6 217.81,53.98 216.53,55.24 215.26,55.24 214,53.98 E4.8 212.72,52.7 212.09,52.07 202.56,52.07 201.29,53.34 D35L1.C | E1.7 214,14.61 215.26,13.34 216.53,13.34 217.81,14.61 E1.5 219.07,14.61 220.34,14.61 E1.4 220.98,13.97 222.25,12.7 229.24,12.7 230.5,13.97 C1.2 | 208.28,99.06 208.28,85.72 C9.2 | 208.28,99.06 208.28,99.69 205.74,99.69 C10.2 | C2.2 230.5,26.67 229.87,26.04 227.97,26.04 226.69,27.3 E2.2 | D35L1.AA 201.29,27.94 202.56,29.21 213.36,29.21 E2.7 | 147.96,57.15 158.75,57.15 159.38,56.52 E14.8 | 147.96,57.15 146.69,55.88 D36L1.A | E12.8 160.66,26.04 161.93,27.3 165.74,27.3 167,26.04 E12.5 | E11.8 160.66,12.06 161.93,10.79 165.74,10.79 167,12.06 E11.5 168.28,12.06 169.54,10.79 180.34,10.79 C11.2 180.97,11.43 182.25,10.16 187.32,10.16 D35L2.SS | C15.2 178.44,71.12 187.32,71.12 E8.7 | E17.13 170.81,93.34 177.8,86.36 177.8,85.72 C16.2 | C12.2 180.97,24.13 182.25,25.4 187.32,25.4 D35L2.CC | C14.2 180.97,54.61 182.25,55.88 187.32,55.88 D35L2.A 188.59,55.88 189.87,57.15 198.75,57.15 200.03,55.88 D35L1.A | D35L2.S 187.32,38.1 182.25,38.1 180.97,36.83 C13.2 180.34,36.2 169.54,36.2 168.28,37.47 E13.5 167,37.47 165.74,36.2 161.93,36.2 160.66,37.47 E13.8 160.02,39.37 147.96,39.37 146.69,38.1 D36L1.S
  Bottom 0.508: 58.42,11.43 132.72,11.43 133.99,12.7 D36L2.PP | 208.28,99.06 190.5,99.06 188.59,100.97 E10.7 | v58.42,62.23 57.78,62.23 56.52,63.5 R15.1 | 58.42,11.43 58.42,10.79 D34L2.SS | 125.73,84.45 123.19,81.92 v107.31,81.92
INIT  (via drill 0.61)
  Top 0.254: E37.2 46.35,75.56 47.62,75.56 E37.1 | v162.56,67.31 165.1,69.85 165.1,71.12 E15.5 | v204.47,57.78 204.47,17.78 213.36,8.89 E1.8
  Bottom 0.254: 148.59,67.31 145.41,64.14 E18.12 | 148.59,67.31 v162.56,67.31 178.44,67.31 184.15,61.59 191.77,61.59 193.04,60.33 201.93,60.33 v204.47,57.78 | E15.4 167,71.75 165.74,71.75 E15.5 | 148.59,67.31 143.51,67.31 142.88,66.67 99.06,66.67 97.79,67.94 81.92,67.94 78.74,71.12 57.15,71.12 57.15,77.47 56.52,78.11 50.16,78.11 48.9,76.83 E37.1
INIT1\  (via drill 0.61)
  Top 0.254: v168.91,3.17 168.91,6.35 163.19,12.06 E11.7 | v218.44,2.54 219.71,3.81 219.71,25.4 220.98,26.67 E2.4
  Bottom 0.254: v168.91,3.17 169.54,2.54 v218.44,2.54
INIT4\  (via drill 0.61)
  Top 0.254: v158.12,4.45 158.12,40.01 160.66,40.01 161.93,38.73 E13.7
  Bottom 0.254: v158.12,4.45 161.29,1.27 225.43,1.27 233.04,8.89 233.04,25.4 226.06,25.4 224.16,27.3 E2.3
INIT\  (via drill 0.61)
  Top 0.254: v96.52,66.67 96.52,69.85 E30.1 | 123.19,38.1 123.19,27.94 124.46,26.67 E21.1 | 123.19,38.1 124.46,39.37 E22.1 | 123.19,53.34 124.46,54.61 E23.1 | 123.19,53.34 123.19,38.1 | v123.19,73.03 123.19,53.34 | E17.3 172.72,100.33 171.45,99.06 v171.45,74.93 172.72,76.2 172.72,77.47 E16.13 173.35,79.38 175.26,81.28 175.26,85.09 E16.1 | v133.35,73.03 133.35,83.82 132.08,85.09 E19.8
  Bottom 0.254: v96.52,66.67 97.16,66.04 106.68,66.04 108.58,64.14 E24.9 | E30.1 97.16,71.75 98.42,73.03 v123.19,73.03 v133.35,73.03 | E19.8 132.72,85.72 133.99,84.45 142.88,84.45 144.15,85.72 E19.3 145.41,85.72 147.32,83.82 172.72,83.82 174.62,85.72 E16.1 | E15.6 163.19,73.03 165.1,74.93 v171.45,74.93 232.41,74.93 232.41,64.14 231.78,63.5 231.14,63.5 231.14,54.61 E4.1
INT_RQ\
  Top 0.254: E33.3 66.04,74.93 64.77,73.66 64.77,45.09 62.23,42.55 62.23,32.38 60.96,31.11 D34L2.Z
  Bottom 0.254: D34L1.Z 70.48,30.48 69.22,29.21 62.87,29.21 61.59,30.48 D34L2.Z
INTR4\
  Top 0.254: E30.3 91.44,69.85 92.71,68.58 92.71,16.51 106.05,3.17 161.29,3.17 161.29,27.94 160.02,29.21 E13.9
IOS\  (via drill 0.61)
  Top 0.254: v59.69,63.5 59.69,37.47 60.96,36.2 D34L2.V
  Bottom 0.254: v59.69,63.5 55.88,67.31 E33.8 | D34L1.V 70.48,35.56 69.22,34.29 62.87,34.29 61.59,35.56 D34L2.V
LCD1
  Top 0.254: E31.2 94.61,85.72 95.89,85.72 E31.1
  Bottom 0.254: E25.6 108.58,85.72 107.31,84.45 101.6,84.45 99.69,86.36 97.16,86.36 E31.1
LCD1\  (via drill 0.61)
  Top 0.254: E24.5 111.76,72.39 113.03,73.66 113.03,80.01 111.76,81.28 111.76,85.09 E25.5 111.76,87.63 v111.76,89.53 | E16.3 170.18,85.09 170.18,82.55 167.64,80.01 E16.11 167.64,77.47 171.45,73.66 v171.45,69.85 171.45,63.5 176.53,58.42 176.53,54.61 179.07,52.07 179.07,31.11 181.61,28.57 181.61,3.17 174.62,3.17 173.35,4.45 E11.14 | v184.15,69.85 182.25,71.75 182.25,84.45 190.5,92.71 E10.9
  Bottom 0.254: v111.76,89.53 113.03,90.81 123.19,90.81 125.09,88.9 160.02,88.9 161.29,87.63 161.93,88.27 168.28,88.27 169.54,87 E16.3 | v171.45,69.85 v184.15,69.85
MAINT  (via drill 0.61)
  Top 0.254: E35.3 42.55,40.01 36.2,33.66 E35.9 35.56,34.29 35.56,39.37 E35.6 35.56,41.91 35.56,46.99 E36.9 35.56,49.53 35.56,54.61 E36.6 | v72.39,58.42 72.39,64.77 v82.55,74.93 82.55,91.44 83.82,92.71 E32.9 | v162.56,74.93 162.56,77.47 E16.9
  Bottom 0.254: 43.81,57.78 45.09,56.52 E36.2 | 43.81,57.78 37.47,57.78 36.2,56.52 E36.6 | v72.39,58.42 71.75,57.78 43.81,57.78 | v162.56,74.93 161.93,74.3 83.19,74.3 v82.55,74.93
MAINT\  (via drill 0.61)
  Top 0.254: v120.65,76.83 120.65,66.04 119.38,64.77 E24.13 | E31.5 86.36,85.09 83.82,82.55 83.82,80.01 E31.9 | v173.99,81.92 173.99,99.06 175.26,100.33 E17.2
  Bottom 0.254: E19.2 146.69,87 145.41,88.27 136.53,88.27 135.25,87 E19.7 133.99,87 132.72,88.27 131.44,88.27 130.81,87.63 130.81,83.19 151.13,83.19 155.57,78.74 | E31.9 84.45,78.11 85.72,76.83 v120.65,76.83 150.5,76.83 152.4,78.74 155.57,78.74 | 155.57,78.74 159.38,78.74 E16.8 160.66,79.38 162.56,81.28 173.35,81.28 v173.99,81.92 209.55,81.92 209.55,99.69 205.74,103.5 200.03,103.5 198.75,102.23 E10.3
MSB8  (via drill 0.61)
  Top 0.254: v111.76,21.59 114.3,19.05 E21.12 114.94,18.41 118.11,21.59 118.11,42.55 120.65,45.09 120.65,53.34 119.38,54.61 E23.3 120.02,55.24 121.28,55.24 E23.2 | v191.77,60.33 191.77,68.58 193.04,69.85 E8.5
  Bottom 0.254: v111.76,21.59 99.06,21.59 96.52,24.13 E27.1 | v191.77,60.33 190.5,59.05 150.5,59.05 149.86,59.69 137.79,59.69 135.89,57.78 123.83,57.78 122.56,56.52 E23.2
MSB12  (via drill 0.61)
  Top 0.254: v110.49,52.07 113.67,48.9 E23.12 | v201.93,59.05 201.93,68.58 200.66,69.85 E8.2 | v129.54,54.61 v126.36,51.44
  Bottom 0.254: E29.1 96.52,54.61 99.06,52.07 v110.49,52.07 125.73,52.07 v126.36,51.44 | v201.93,59.05 201.29,58.42 167.64,58.42 166.37,57.15 166.37,51.44 152.4,51.44 149.22,54.61 v129.54,54.61
MYDEV\
  Top 0.254: 168.91,22.86 168.91,15.24 170.18,13.97 E11.4 | 168.91,22.86 170.18,24.13 E12.4 | 168.91,22.86 168.91,35.56 170.18,36.83 E13.4
  Bottom 0.254: E13.4 169.54,38.73 167.64,40.64 163.19,40.64 IOT.1
N$1
  Top 0.254: E14.9 160.02,46.99 160.02,46.35 76.1
N$2
  Bottom 0.254: E29.9 84.45,47.62 85.72,46.35 117.47,46.35 118.75,47.62 E23.14
N$3  (via drill 0.61)
  Top 0.254: E27.10 86.36,19.05 86.36,24.13 E27.5 86.36,26.67 86.36,31.75 E28.10 86.36,34.29 86.36,39.37 E28.5 | v73.03,19.05 73.03,6.35 57.78,6.35 57.15,6.99 57.15,20.32 45.72,31.75 E35.13 | E27.13 93.98,19.05 93.98,24.13 E27.2 93.98,26.67 93.98,31.75 E28.13 93.98,34.29 93.98,39.37 E28.2 93.98,41.91 v93.98,43.81 | v118.11,43.81 118.11,68.58 119.38,69.85 E24.2
  Bottom 0.254: v73.03,19.05 77.47,23.5 84.45,23.5 85.72,24.77 E27.5 87,24.77 88.27,23.5 92.08,23.5 93.34,24.77 E27.2 | v93.98,43.81 v118.11,43.81
N$4  (via drill 0.61)
  Top 0.254: v36.83,79.38 36.83,74.93 34.29,72.39 34.29,31.11 38.73,31.11 40.01,32.38 E35.11
  Bottom 0.254: v36.83,79.38 45.09,87.63 74.93,87.63 80.64,93.34 E32.8
N$5
  Top 0.254: E14.15 175.26,46.99 175.26,46.35 70.1
N$6
  Top 0.254: E14.14 172.72,46.99 172.72,46.35 71.1
N$7
  Top 0.254: E14.13 170.18,46.99 170.18,46.35 72.1
N$8
  Top 0.254: E14.12 167.64,46.99 167.64,46.35 73.1
N$9
  Top 0.254: E14.11 165.1,46.99 165.1,46.35 74.1
N$10
  Top 0.254: E14.10 162.56,46.99 162.56,46.35 75.1
N$11  (via drill 0.61)
  Top 0.254: v158.75,52.7 157.48,51.44 157.48,46.35 77.1
  Bottom 0.254: v158.75,52.7 159.38,52.7 161.93,55.24 E14.7
N$12  (via drill 0.61)
  Top 0.254: E29.13 93.98,49.53 93.98,54.61 E29.2 | E29.10 86.36,49.53 86.36,54.61 E29.5 | v115.57,60.33 115.57,64.77 116.2,65.41 116.2,69.22 116.84,69.85 E24.3
  Bottom 0.254: v115.57,60.33 114.3,59.05 89.53,59.05 87,56.52 E29.5 | E29.2 93.34,55.24 87,48.9 E29.10
N$13
  Top 0.254: E38.1 48.26,100.33 48.26,100.97 PAD10.1
N$14
  Top 0.254: E38.2 45.72,100.33 45.72,100.97 PAD11.1
N$15
  Top 0.254: E38.3 43.18,100.33 43.18,100.97 PAD12.1
N$16
  Top 0.254: E38.4 40.64,100.33 40.64,100.97 PAD13.1
N$17
  Top 0.254: E38.5 38.1,100.33 38.1,100.97 PAD14.1
N$18
  Top 0.254: E38.6 35.56,100.33 35.56,100.97 PAD15.1
N$19
  Top 0.254: E38.7 33.02,100.33 33.02,100.97 PAD16.1
N$20
  Top 0.254: E38.8 30.48,100.33 30.48,100.97 PAD17.1
N$21
  Top 0.254: E4.5 220.98,54.61 222.25,55.88 222.25,68.58 223.52,69.85 E5.3
N$22  (via drill 0.61)
  Top 0.254: v143.51,66.04 143.51,80.01 146.05,82.55 146.05,95.89 144.15,95.89 142.88,94.61 E20.11
  Bottom 0.254: 142.88,65.41 143.51,64.77 143.51,60.96 155.57,60.96 158.75,64.14 158.75,66.67 160.66,66.67 161.93,65.41 E15.9 | 142.88,65.41 142.24,66.04 114.3,66.04 112.39,64.14 E24.10 | 142.88,65.41 v143.51,66.04
N$23
  Top 0.254: E38.16 48.26,90.17 48.26,89.53 PAD20.1
N$24
  Top 0.254: E38.15 45.72,90.17 45.72,89.53 PAD21.1
N$25
  Top 0.254: E38.14 43.18,90.17 43.18,89.53 PAD22.1
N$26
  Top 0.254: E38.13 40.64,90.17 40.64,89.53 PAD23.1
N$27
  Top 0.254: E38.12 38.1,90.17 38.1,89.53 PAD24.1
N$28
  Top 0.254: E38.11 35.56,90.17 35.56,89.53 PAD25.1
N$29
  Top 0.254: E38.10 33.02,90.17 33.02,89.53 PAD26.1
N$30
  Top 0.254: E38.9 30.48,90.17 30.48,89.53 PAD27.1
N$31  (via drill 0.61)
  Top 0.254: E21.2 121.28,24.77 120.02,24.77 E21.3 119.38,26.67 120.65,27.94 v120.65,35.56 | v99.06,32.38 97.79,33.66 97.79,34.29 97.16,34.92 97.16,38.73 96.52,39.37 E28.1 | v114.3,36.83 114.3,34.29 E22.12
  Bottom 0.254: v99.06,32.38 101.6,34.92 112.39,34.92 113.67,33.66 E22.12 | v120.65,35.56 120.02,36.2 114.94,36.2 v114.3,36.83
N$32  (via drill 0.61)
  Top 0.254: v116.84,60.33 116.84,62.23 E24.12 | v158.12,60.33 160.02,62.23 160.02,63.5 E15.8
  Bottom 0.254: v116.84,60.33 v158.12,60.33
N$33  (via drill 0.61)
  Top 0.254: v101.6,57.78 104.78,54.61 v104.78,49.53
  Bottom 0.254: v101.6,57.78 90.81,57.78 89.53,56.52 E29.4 | v104.78,49.53 105.41,50.16 114.94,50.16 116.2,48.9 E23.13
N$34
  Top 0.254: E40.1 25.4,100.33 25.4,100.97 PAD18.1
N$35
  Bottom 0.254: E5.11 221.62,64.14 227.97,70.48 E5.1
N$37
  Top 0.254: E8.13 200.66,64.77 198.12,67.31 198.12,69.85 E8.3
  Bottom 0.254: E15.3 170.81,71.75 172.09,70.48 175.9,70.48 176.53,71.12 176.53,73.03 196.22,73.03 197.49,71.75 E8.3
N$38
  Bottom 0.254: E8.11 196.22,62.87 197.49,62.87 E8.12
N$39
  Top 0.254: E8.9 190.5,64.77 190.5,69.85 E8.6
N$40  (via drill 0.61)
  Top 0.254: v185.42,60.33 185.42,59.05 191.77,59.05 193.04,60.33 193.04,62.23 E8.10
  Bottom 0.254: v185.42,60.33 184.78,60.96 171.45,60.96 168.28,64.14 E15.11
N$41
  Top 0.254: E40.2 22.86,100.33 22.86,100.97 PAD19.1
N$42
  Top 0.254: 158.75,106.05 158.75,96.52 160.02,95.25 E17.9 | 158.75,106.05 158.75,113.03 55.24,113.03 44.45,102.23 44.45,97.79 41.91,95.25 41.91,88.27 38.1,84.45 38.1,77.47 E37.5 | 158.75,106.05 175.9,106.05 179.07,102.87 179.07,99.69 181.61,97.16 181.61,71.12 187.96,64.77 E8.8
  Bottom 0.254: E17.12 167,93.34 165.74,92.08 161.93,92.08 160.66,93.34 E17.9
N$43
  Top 0.254: E40.3 20.32,100.33 20.32,100.97 PAD28.1
N$44  (via drill 0.61)
  Top 0.254: v102.23,69.22 100.97,70.48 100.97,97.16 99.06,99.06 96.52,99.06 96.52,100.33 E32.1
  Bottom 0.254: v102.23,69.22 107.31,69.22 108.58,70.48 E24.6
N$45
  Top 0.254: E1.11 220.98,6.35 220.34,5.71 220.34,3.17 218.44,1.27 217.17,1.27 217.17,25.4 215.9,26.67 E2.6
N$46  (via drill 0.61)
  Top 0.254: v155.57,97.79 v155.57,62.23
  Bottom 0.254: v155.57,62.23 154.94,61.59 149.22,61.59 147.96,62.87 E18.13 | v155.57,97.79 158.75,100.97 159.38,100.97 E17.8
N$47
  Top 0.254: E1.6 215.9,13.97 215.9,8.89 E1.9
  Bottom 0.254: E1.9 216.53,6.99 217.81,6.99 E1.10
N$48
  Top 0.254: E4.10 215.9,46.99 215.9,52.07 E4.7 | E4.3 225.43,52.7 224.16,52.7 E4.4 223.52,54.61 223.52,57.78 R19.2
  Bottom 0.254: E4.7 216.53,52.7 217.81,51.44 221.62,51.44 222.88,52.7 E4.4
N$49  (via drill 0.61)
  Top 0.508: E14.5 168.28,55.24 169.54,55.24 E14.4 | v185.42,5.71 182.88,8.26 v182.88,48.9
  Bottom 0.508: v185.42,5.71 221.62,5.71 222.88,6.99 E1.12 | v182.88,48.9 179.71,52.07 173.99,52.07 170.81,55.24 E14.4
N$50
  Top 0.254: E40.4 17.78,100.33 17.78,100.97 PAD29.1
N$51
  Top 0.254: E40.5 15.24,100.33 15.24,100.97 PAD30.1
N$52
  Top 0.254: E40.6 12.7,100.33 12.7,100.97 PAD31.1
N$53
  Top 0.254: E40.7 10.16,100.33 10.16,100.97 PAD32.1
N$54
  Top 0.254: E40.8 7.62,100.33 7.62,100.97 PAD33.1
N$55
  Top 0.254: E40.16 25.4,90.17 25.4,89.53 PAD34.1
N$56
  Top 0.254: E40.15 22.86,90.17 22.86,89.53 PAD35.1
N$57
  Top 0.254: E40.14 20.32,90.17 20.32,89.53 PAD36.1
N$58
  Top 0.254: E40.13 17.78,90.17 17.78,89.53 PAD37.1
N$59
  Top 0.254: E40.12 15.24,90.17 15.24,89.53 PAD38.1
N$60
  Bottom 0.254: E29.12 92.08,48.9 93.98,50.8 119.38,50.8 121.28,48.9 E23.15
N$61
  Top 0.254: E40.11 12.7,90.17 12.7,89.53 PAD39.1
N$62  (via drill 0.61)
  Top 0.254: v90.17,14.61 90.17,22.86 88.9,24.13 E27.4
  Bottom 0.254: v90.17,14.61 90.81,15.24 119.38,15.24 120.65,16.51 120.65,19.05 120.02,19.68 118.75,19.68 117.47,18.41 E21.13
N$63
  Bottom 0.254: E27.9 84.45,17.14 85.72,15.88 117.47,15.88 118.75,17.14 E21.14
N$64
  Bottom 0.254: E27.12 92.08,18.41 93.98,20.32 120.65,20.32 121.92,19.05 E21.15
N$65
  Bottom 0.254: E28.12 92.08,33.66 93.34,34.92 97.79,34.92 98.42,35.56 119.38,35.56 121.28,33.66 E22.15
N$66  (via drill 0.61)
  Top 0.254: v111.76,38.1 113.03,36.83 113.03,30.48 115.57,27.94 116.84,27.94 116.84,31.75 E22.13
  Bottom 0.254: v111.76,38.1 98.42,38.1 97.79,38.73 90.81,38.73 89.53,40.01 E28.4
N$67
  Bottom 0.254: E28.9 84.45,32.38 85.72,31.11 117.47,31.11 118.75,32.38 E22.14
N$68
  Top 0.254: E40.10 10.16,90.17 10.16,89.53 PAD40.1
N$69
  Top 0.254: E40.9 7.62,90.17 7.62,89.53 PAD41.1
N$70
  Top 0.254: E39.1 25.4,77.47 25.4,78.11 PAD42.1
N$71
  Top 0.254: E39.2 22.86,77.47 22.86,78.11 PAD43.1
N$72
  Top 0.254: E39.3 20.32,77.47 20.32,78.11 PAD44.1
N$73
  Top 0.254: E39.4 17.78,77.47 17.78,78.11 PAD45.1
N$74
  Top 0.254: E39.5 15.24,77.47 15.24,78.11 PAD46.1
N$75
  Top 0.254: E39.6 12.7,77.47 12.7,78.11 PAD47.1
N$76
  Top 0.254: E39.7 10.16,77.47 10.16,78.11 PAD48.1
N$77
  Top 0.254: E39.8 7.62,77.47 7.62,78.11 PAD49.1
N$78
  Top 0.254: E39.16 25.4,67.31 25.4,66.67 PAD50.1
N$79
  Top 0.254: E39.15 22.86,67.31 22.86,66.67 PAD51.1
N$80
  Top 0.254: E39.14 20.32,67.31 20.32,66.67 PAD52.1
N$81
  Top 0.254: E39.13 17.78,67.31 17.78,66.67 PAD53.1
N$82
  Top 0.254: E39.12 15.24,67.31 15.24,66.67 PAD54.1
N$83
  Top 0.254: E39.11 12.7,67.31 12.7,66.67 PAD55.1
N$84
  Top 0.254: E39.10 10.16,67.31 10.16,66.67 PAD56.1
N$85
  Top 0.254: E39.9 7.62,67.31 7.62,66.67 PAD57.1
N$86  (via drill 0.61)
  Top 0.254: v68.58,72.39 68.58,74.93 E33.2
  Bottom 0.254: v68.58,72.39 69.22,73.03 84.45,73.03 85.72,71.75 E30.5
N$87
  Top 0.254: E32.5 87,100.97 88.27,100.97 E32.4 88.9,100.33 88.9,97.79 91.44,95.25 E32.12
N$88
  Bottom 0.254: E20.6 137.79,100.97 139.06,99.69 145.41,99.69 146.69,100.97 E20.2
N$89  (via drill 0.61)
  Top 0.254: E33.9 59.05,67.94 60.33,67.94 E33.10 60.96,69.85 62.23,71.12 62.23,86.36 v81.92,106.05 | v144.15,104.78 144.15,103.5 144.78,102.87 E20.3
  Bottom 0.254: v144.15,104.78 142.88,106.05 v81.92,106.05
N$90
  Top 0.254: E26.6 109.86,102.23 117.47,109.86 133.35,109.86 133.35,91.44 137.16,87.63 E19.6
N$91  (via drill 0.61)
  Top 0.254: v121.92,107.95 116.84,102.87 E26.3 | v146.69,107.95 151.13,103.5 151.13,88.9 149.86,87.63 E19.1
  Bottom 0.254: v121.92,107.95 v146.69,107.95
N$92
  Top 0.254: E18.3 144.78,72.39 144.78,77.47 E19.14
N$93
  Top 0.254: E18.6 137.16,72.39 134.62,74.93 134.62,77.47 E19.10
N$94  (via drill 0.61)
  Top 0.254: E33.6 58.42,77.47 58.42,80.64 R18.1 | v90.17,73.03 90.17,66.04 88.9,64.77 E30.11
  Bottom 0.254: v90.17,73.03 89.53,73.66 60.96,73.66 59.05,75.56 E33.6
N$95
  Bottom 0.254: E33.5 61.59,76.83 62.87,78.11 80.64,78.11 E31.8
N$96  (via drill 0.61)
  Top 0.254: v154.31,90.81 154.31,85.09 151.13,81.92 151.13,69.85 148.59,67.31 148.59,61.59 139.06,61.59 137.79,62.87 E18.9
  Bottom 0.254: v154.31,90.81 159.38,95.89 170.81,95.89 172.09,94.61 E17.14
N$97  (via drill 0.61)
  Top 0.254: v107.95,107.31 107.95,96.52 106.68,95.25 E26.8
  Bottom 0.254: v107.95,107.31 108.58,106.68 171.45,106.68 174.62,103.5 175.9,103.5 177.16,102.23 E17.1
N$98  (via drill 0.61)
  Top 0.254: v66.67,81.28 66.67,80.64 63.5,77.47 E33.4
  Bottom 0.254: v66.67,81.28 69.85,84.45 81.92,84.45 83.19,85.72 E31.6
N$99
  Bottom 0.254: E30.13 94.61,64.14 95.89,65.41 104.78,65.41 106.05,64.14 E24.8
N$100
  Top 0.508: E25.10 111.76,80.01 110.49,81.28 110.49,90.17 112.39,92.08 116.2,92.08 116.2,93.34 E26.12
  Bottom 0.508: E26.12 117.47,93.34 118.75,93.34 E26.13
N$101  (via drill 0.61)
  Top 0.508: E36.11 41.27,47.62 42.55,47.62 E36.12 | v114.3,75.56 114.3,76.2 116.2,78.11 E25.12 | v85.72,75.56 82.55,72.39 82.55,69.85 v74.93,62.23 | v63.5,60.96 62.87,60.33 v62.87,45.72
  Bottom 0.508: v85.72,75.56 v114.3,75.56 | v74.93,62.23 64.77,62.23 v63.5,60.96 | v62.87,45.72 61.59,46.99 49.53,46.99 48.9,46.35 45.09,46.35 43.81,47.62 E36.12
N$102
  Bottom 0.254: E31.13 94.61,79.38 96.52,81.28 104.14,81.28 106.05,79.38 E25.8
N$104
  Bottom 0.254: E10.6 191.13,100.97 192.41,99.69 201.29,99.69 202.56,100.97 E10.1
N$105
  Top 0.254: E10.10 193.68,93.34 194.94,93.34 E10.11 196.22,93.34 197.49,93.34 E10.12
N$106  (via drill 0.61)
  Top 0.254: E37.12 43.81,67.94 45.09,67.94 E37.13 | v172.09,111.12 187.96,95.25 E10.8 | v57.15,106.05 49.53,98.42 49.53,95.89 52.07,93.34 v52.07,64.77
  Bottom 0.254: v172.09,111.12 62.23,111.12 v57.15,106.05 | v52.07,64.77 50.8,66.04 46.99,66.04 45.72,67.31 E37.13
PARITY
  Top 0.254: E15.13 172.72,66.04 172.72,71.12 E15.2 173.35,71.75 174.62,71.75 E15.1
  Bottom 0.254: E4.15 228.6,46.99 228.6,51.44 227.97,51.44 227.33,52.07 227.33,68.58 228.6,68.58 229.87,69.85 229.87,73.66 175.26,73.66 E15.1
PARITY\
  Top 0.254: E17.10 162.56,92.71 163.83,91.44 163.83,76.2 166.37,73.66 166.37,69.85 170.18,66.04 E15.12
RD  (via drill 0.61)
  Top 0.254: v52.07,35.56 54.61,38.1 v54.61,81.28
  Bottom 0.254: v52.07,35.56 40.64,35.56 38.73,33.66 E35.10 | v54.61,81.28 60.33,87 79.38,87 85.72,93.34 E32.10 86.36,92.71 87.63,92.71 87.63,85.09 88.9,83.82 107.95,83.82 108.58,84.45 120.02,84.45 121.28,85.72 E25.1
RUN
  Top 0.254: E33.12 66.67,67.94 67.94,67.94 E33.13
  Bottom 0.254: E33.13 69.22,67.94 70.48,66.67 80.64,66.67 83.19,64.14 E30.9 84.45,62.87 85.72,61.59 140.34,61.59 141.6,62.87 E18.11
RX_12_BIT\
  Top 0.254: E37.8 33.02,67.31 29.21,63.5 29.21,28.57 26.67,26.04 26.67,24.77 25.4,23.5 R16.2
